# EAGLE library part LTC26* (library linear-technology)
Dual 16-/14-/12-Bit Rail-to-Rail DACs Source: www.linear.com

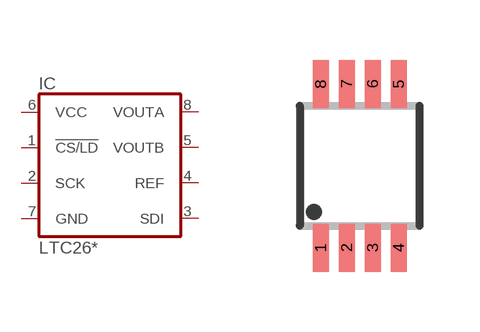
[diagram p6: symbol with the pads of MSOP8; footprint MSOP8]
Designator prefix IC

## LTC2602CMS8, LTC2602IMS8, LTC2612CMS8, LTC2612IMS8, LTC2622CMS8, LTC2622IMS8  [MSOP8]
1  !CS/LD  in
2  SCK  in
3  SDI  in
4  REF  in
5  VOUTB  out
6  VCC  pwr
7  GND  pwr
8  VOUTA  out

## Footprint MSOP8 (pad centres in mm)
MSOP8
smd 0.4 x 1.2: 1 -0.975,-2.05; 2 -0.325,-2.05; 3 0.325,-2.05; 4 0.975,-2.05; 5 0.975,2.05; 6 0.325,2.05; 7 -0.325,2.05; 8 -0.975,2.05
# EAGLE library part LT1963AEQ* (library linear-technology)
LT1963 1.5A, Low Noise, Fast Transient Response LDO Regulator Source: http://www.linear.com

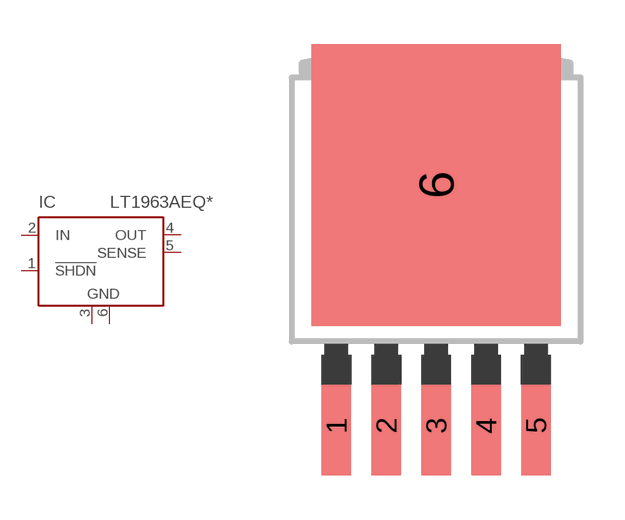
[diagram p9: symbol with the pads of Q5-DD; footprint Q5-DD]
Designator prefix IC

## LT1963AEQ, LT1963AEQ-1.5, LT1963AEQ-1.8, LT1963AEQ-2.5, LT1963AEQ-3.3  [Q5-DD]
1  !SHDN  in
2  IN  in
3  GND  pwr
4  OUT  pas
5  SENSE  in
6  GND  pwr

## Footprint Q5-DD (pad centres in mm)
Q5-DD
smd 1 x 3.4: 1 -3.4,-7.875; 2 -1.7,-7.875; 3 0,-7.875; 4 1.7,-7.875; 5 3.4,-7.875
smd 8.5 x 9.6: 6 0,0.325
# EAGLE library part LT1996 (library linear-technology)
Precision, 100µA Gain Selectable Amplifier Difference Amplifier, Gain Range 9 to 117, CMRR >80dB Source: http://www.linear.com

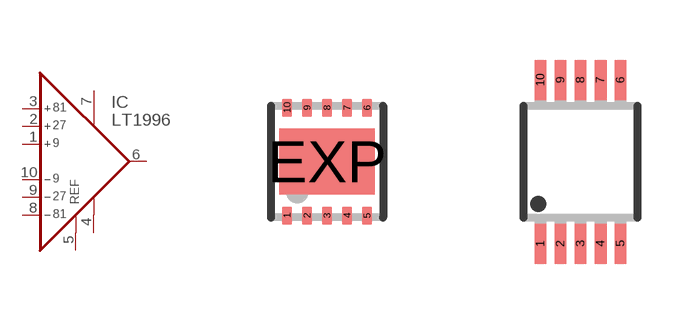
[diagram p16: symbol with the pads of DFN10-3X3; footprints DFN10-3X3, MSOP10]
Designator prefix IC

## LT1996ACDD, LT1996AIDD, LT1996CDD, LT1996IDD  [DFN10-3X3]
1  P9  in
2  P27  in
3  P81  in
4  V-  pwr
5  REF  in
6  OUT  out
7  V+  pwr
8  M81  in
9  M27  in
10  M9  in

## LT1996ACMS, LT1996AIMS, LT1996CMS, LT1996IMS  [MSOP10]
Pads as for DFN10-3X3

## Footprint DFN10-3X3 (pad centres in mm)
DD Package 10-Lead Plastic DFN (3mm × 3mm) (Reference LTC DWG # 05-08-1669) Source: http://www.linear.com .. 4062fa.pdf
smd 0.25 x 0.45: 1 -1,-1.35; 2 -0.5,-1.35; 3 0,-1.35; 4 0.5,-1.35; 5 1,-1.35; 6 1,1.35; 7 0.5,1.35; 8 0,1.35; 9 -0.5,1.35; 10 -1,1.35
smd 2.38 x 1.65: EXP 0,0

## Footprint MSOP10 (pad centres in mm)
10 Lead Platic MSOP Source: http://www.linear.com .. LT1996
smd 0.3 x 1: 1 -1,-2.05; 2 -0.5,-2.05; 3 0,-2.05; 4 0.5,-2.05; 5 1,-2.05; 6 1,2.05; 7 0.5,2.05; 8 0,2.05; 9 -0.5,2.05; 10 -1,2.05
